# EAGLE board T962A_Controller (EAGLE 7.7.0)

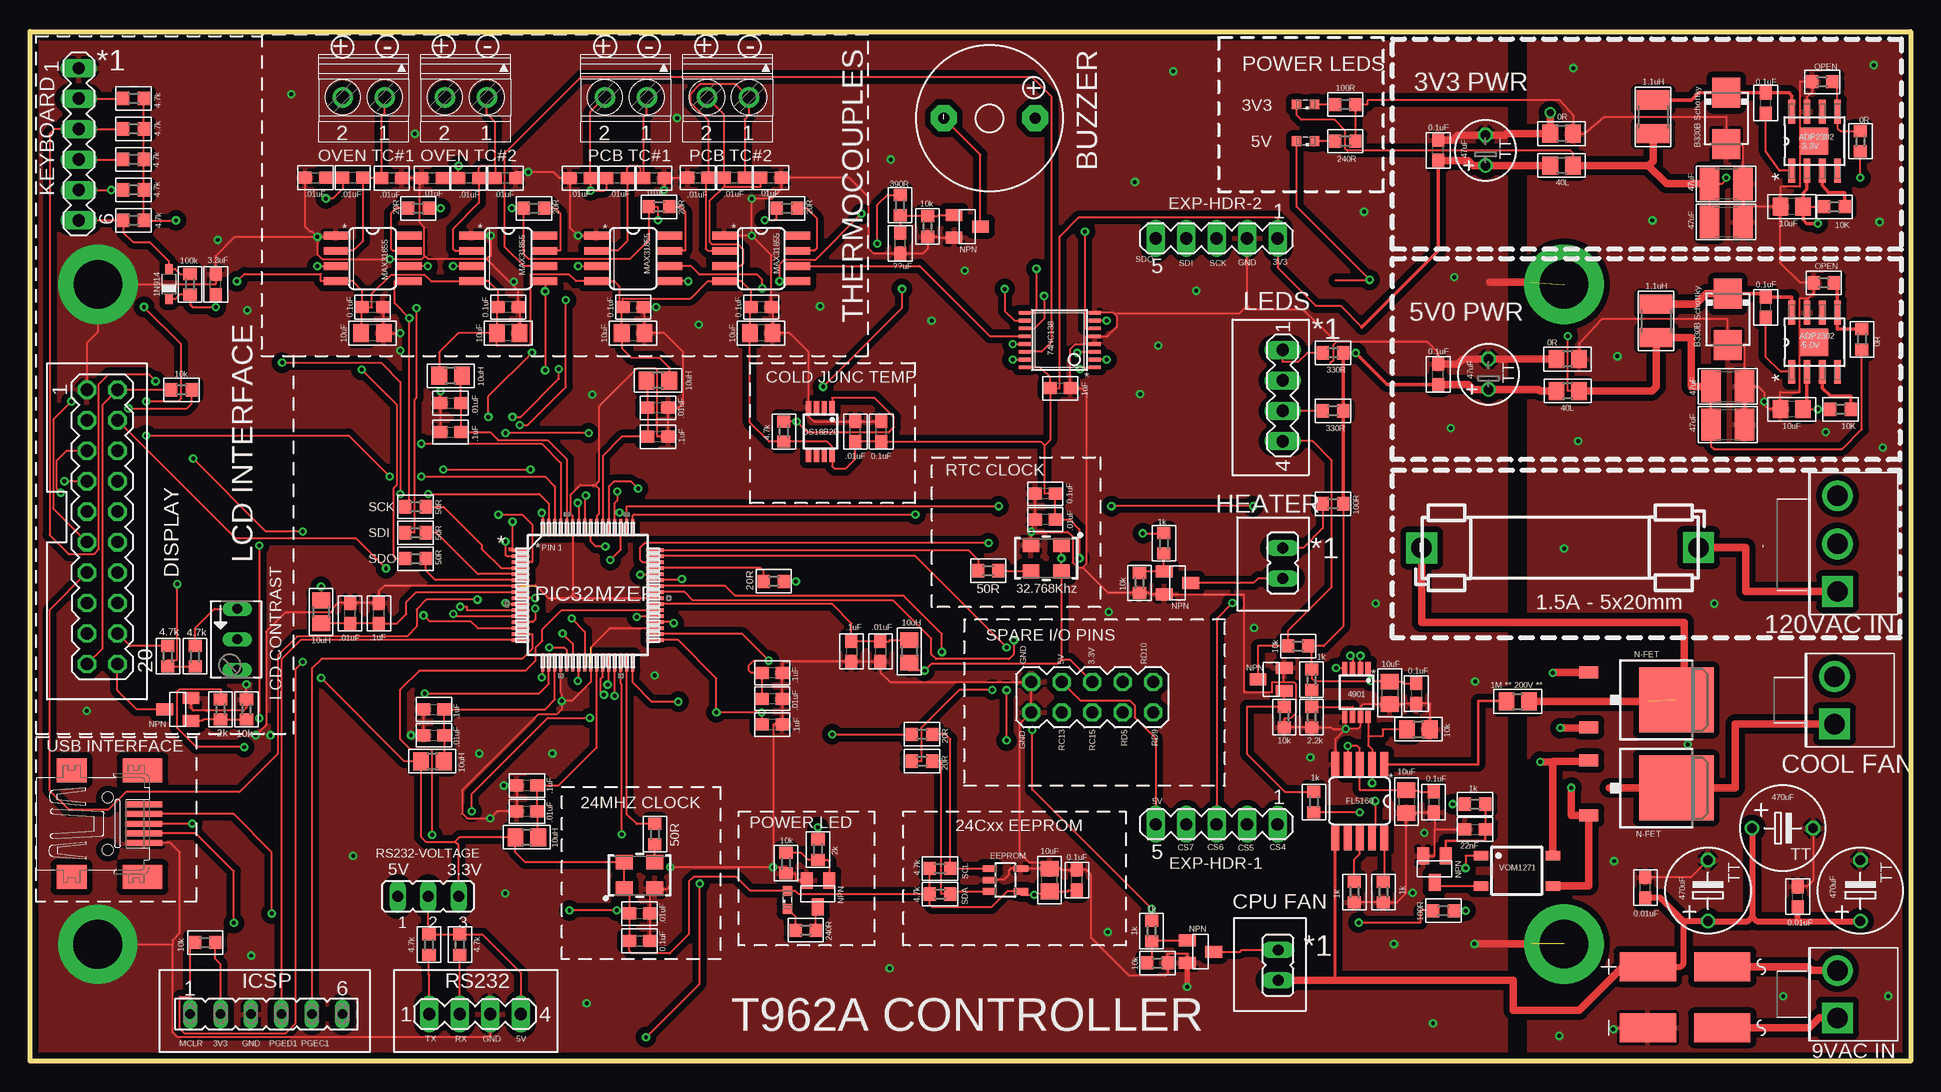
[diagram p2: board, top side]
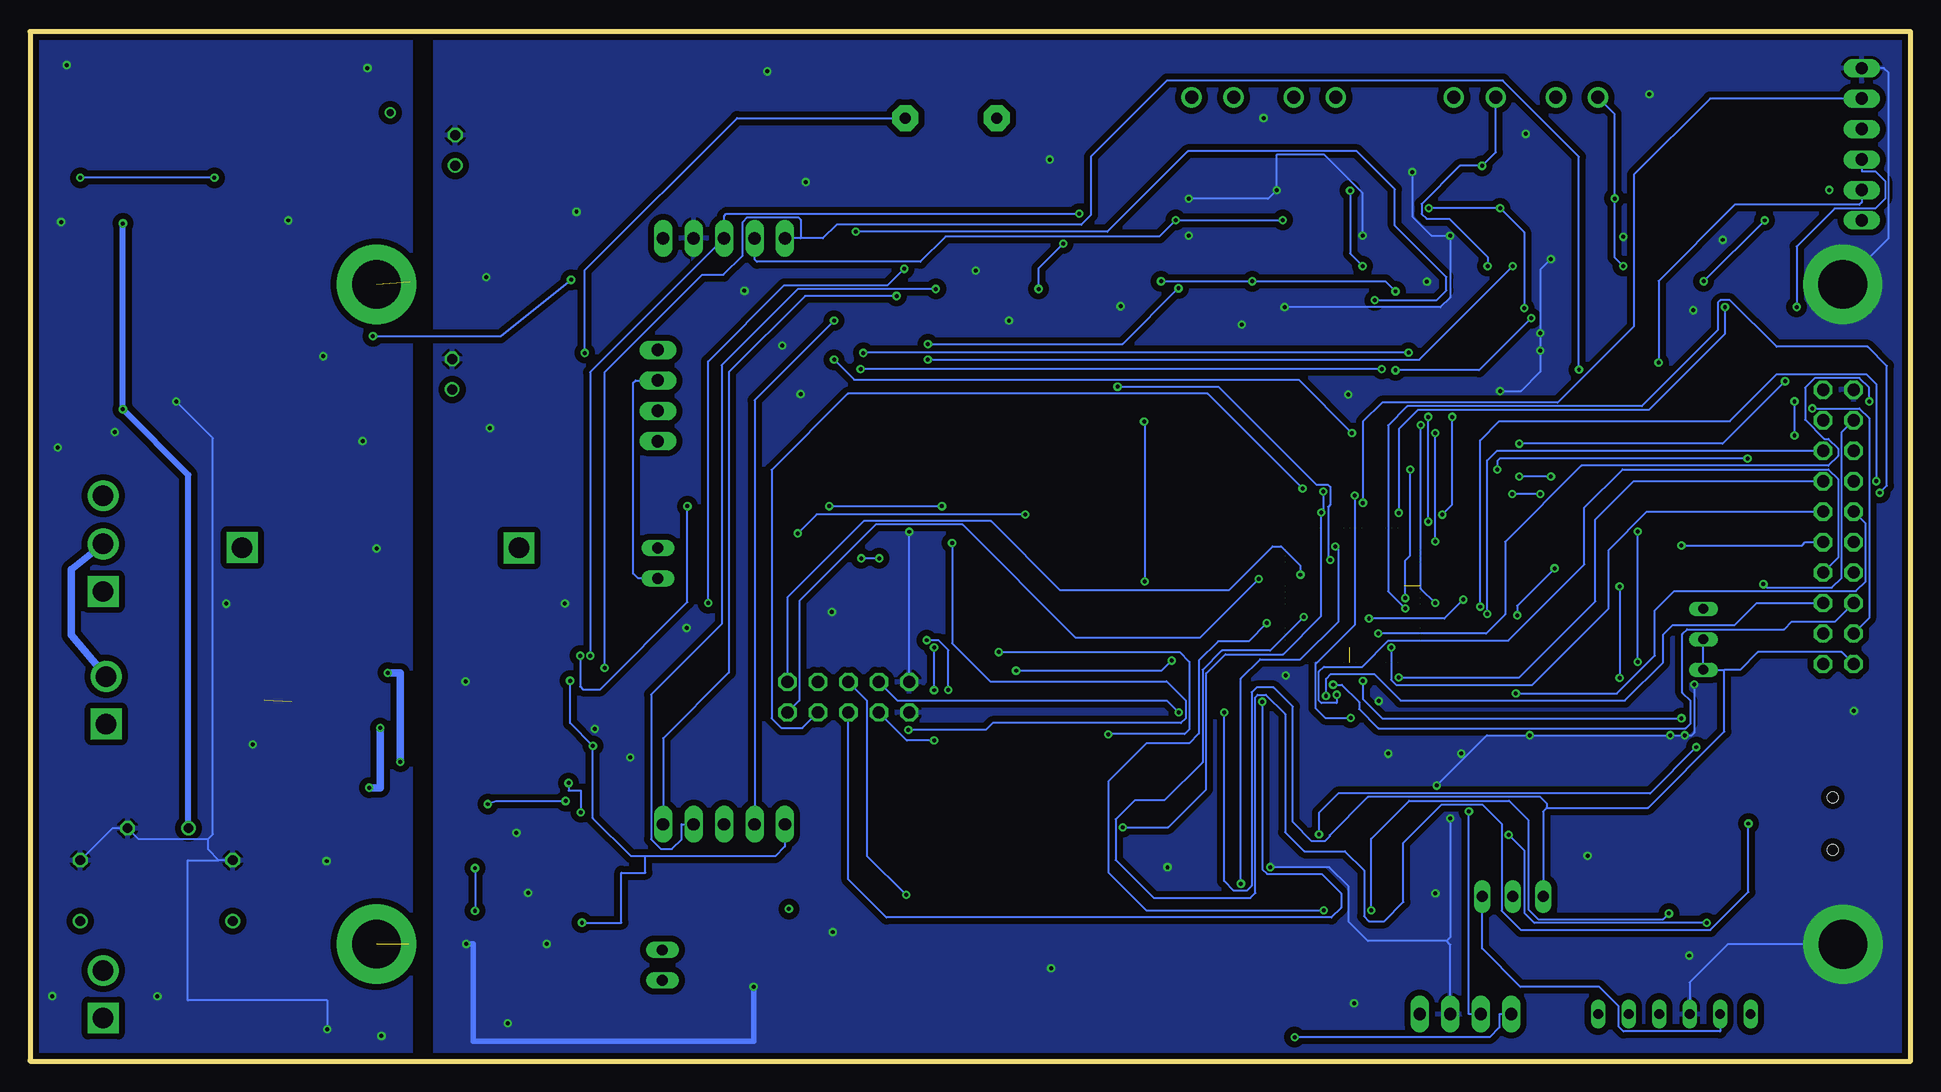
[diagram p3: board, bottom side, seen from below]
Size 156.72 x 86.03 mm. Coordinates in mm from the lower left corner, seen from the top.
Outline: 0,85.9 0.02,86.03 0.02,0 156.72,0.13
Outline: 0,85.9 0,0.05 156.72,0.05 156.72,0.13
Outline: 0,85.9 156.72,85.9 156.72,0.13
Copper layers (1*16): Top 0.035559375mm / dielectric 1.6mm / Bottom 0.035559375mm
Design rules "oshpark-2layer *": minimum track width 6mil, minimum drill 10mil, track to track 6mil, track to pad 6mil, pad to pad 6mil, via to via 6mil, smd to smd 6mil, copper to edge 15mil, drill to drill 6mil, minimum pad ring 5mil, minimum via ring 5mil, stop-mask expansion 2.5mil, vias tented up to drill 13mil, thermal gap 10mil
Net classes: 1 POWER: width 0.305 mm, clearance 0.305 mm

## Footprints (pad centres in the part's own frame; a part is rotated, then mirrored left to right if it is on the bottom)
Z4-D = smd 2.4 x 4.7: AC1 2.55,-3.1; AC2 -2.55,-3.1; VDD 2.55,3.1; VSS -2.55,3.1
TT5D7 = drill 0.813: + -2.54,0 | drill 0.813 octagon: - 2.54,0
C1210 = smd 1.6 x 2.7: 1 -1.4,0; 2 1.4,0
TT2D5 = drill 0.813: + -1.27,0 | drill 0.813 octagon: - 1.27,0
C0603 = smd 1.1 x 1: 1 -0.85,0; 2 0.85,0
C0805 = smd 1.3 x 1.5: 1 -0.95,0; 2 0.95,0
SOD323_ST = smd 0.8 x 0.6: A 1.25,0; C -1.25,0
FUSE_HOLDER_5X20MM_1.78MM = drill 1.707 square: 1 -2.565,0; 2 20.498,0.025
MSOP8 = smd 0.45 x 1: 1 -0.975,-2.05; 2 -0.325,-2.05; 3 0.325,-2.05; 4 0.975,-2.05; 5 0.975,2.05; 6 0.325,2.05; 7 -0.325,2.05; 8 -0.975,2.05
TSSOP16 = smd 0.305 x 0.991: 1 -2.275,-2.918; 2 -1.625,-2.918; 3 -0.975,-2.918; 4 -0.325,-2.918; 5 0.325,-2.918; 6 0.975,-2.918; 7 1.625,-2.918; 8 2.275,-2.918; 9 2.275,2.918; 10 1.625,2.918; 11 0.975,2.918; 12 0.325,2.918; 13 -0.325,2.918; 14 -0.975,2.918; 15 -1.625,2.918; 16 -2.275,2.918
SOT23-5L = smd 0.55 x 1.2: 1 -0.95,-1.3; 2 0,-1.3; 3 0.95,-1.3; 4 0.95,1.3; 5 -0.95,1.3
FE06 = drill 0.813 long: 1 -6.35,0; 2 -3.81,0; 3 -1.27,0; 4 1.27,0; 5 3.81,0; 6 6.35,0
KK41791-4020_3-PIN = drill 1.707 square: 1 -1.981,0 | drill 1.707: 2 1.981,0; 3 5.994,0
KK41791-4020_2-PIN = drill 1.707 square: 1 -1.981,0 | drill 1.707: 2 1.981,0
JP1 = drill 0.914 long: 1 0,-1.27; 2 0,1.27
JP2 = drill 0.914 long: 1 -2.54,0; 2 0,0; 3 2.54,0
L0805 = smd 1.3 x 1.5: 1 -0.95,0; 2 0.95,0
R1210 = smd 1.6 x 2.7: 1 -1.4,0; 2 1.4,0
SML0603 = smd 0.8 x 0.8: A 0.75,0; C -0.75,0
R0603 = smd 1 x 1.1: 1 -0.85,0; 2 0.85,0
R0805 = smd 1.3 x 1.5: 1 -0.95,0; 2 0.95,0
B64Y = drill 0.813 long: A 2.54,0; E -2.54,0; S 0,0
YHE12-XX-7.6MM = drill 0.914 pad 2.159 octagon: + 3.81,0.025; - -3.81,0.025
MA10-2 = drill 1.016 octagon: 1 -11.43,-1.27; 2 -11.43,1.27; 3 -8.89,-1.27; 4 -8.89,1.27; 5 -6.35,-1.27; 6 -6.35,1.27; 7 -3.81,-1.27; 8 -3.81,1.27; 9 -1.27,-1.27; 10 -1.27,1.27; 11 1.27,-1.27; 12 1.27,1.27; 13 3.81,-1.27; 14 3.81,1.27; 15 6.35,-1.27; 16 6.35,1.27; 17 8.89,-1.27; 18 8.89,1.27; 19 11.43,-1.27; 20 11.43,1.27
MA06-1 = drill 1.016 long: 1 -6.35,0; 2 -3.81,0; 3 -1.27,0; 4 1.27,0; 5 3.81,0; 6 6.35,0
MA04-1 = drill 1.016 long: 1 -3.81,0; 2 -1.27,0; 3 1.27,0; 4 3.81,0
MA05-2 = drill 1.016 octagon: 1 -5.08,-1.27; 2 -5.08,1.27; 3 -2.54,-1.27; 4 -2.54,1.27; 5 0,-1.27; 6 0,1.27; 7 2.54,-1.27; 8 2.54,1.27; 9 5.08,-1.27; 10 5.08,1.27
MA05-1 = drill 1.016 long: 1 -5.08,0; 2 -2.54,0; 3 0,0; 4 2.54,0; 5 5.08,0
SOT23-BEC = smd 1 x 1.4: B -0.95,-1.1; C 0,1.1; E 0.95,-1.1
SOIC127P600X175-9N = smd 1.981 x 0.559: 1 -2.464,1.905; 2 -2.464,0.635; 3 -2.464,-0.635; 4 -2.464,-1.905; 5 2.464,-1.905; 6 2.464,-0.635; 7 2.464,0.635; 8 2.464,1.905 | smd 2.286 x 2.286: 9 0,0
TQFP64_10X10MC = smd 1.473 x 0.279: 1 -5.613,3.75; 2 -5.613,3.25; 3 -5.613,2.75; 4 -5.613,2.25; 5 -5.613,1.75; 6 -5.613,1.25; 7 -5.613,0.75; 8 -5.613,0.25; 9 -5.613,-0.25; 10 -5.613,-0.75; 11 -5.613,-1.25; 12 -5.613,-1.75; 13 -5.613,-2.25; 14 -5.613,-2.75; 15 -5.613,-3.25; 16 -5.613,-3.75; 33 5.613,-3.75; 34 5.613,-3.25; 35 5.613,-2.75; 36 5.613,-2.25; 37 5.613,-1.75; 38 5.613,-1.25; 39 5.613,-0.75; 40 5.613,-0.25; 41 5.613,0.25; 42 5.613,0.75; 43 5.613,1.25; 44 5.613,1.75; 45 5.613,2.25; 46 5.613,2.75; 47 5.613,3.25; 48 5.613,3.75 | smd 0.279 x 1.473: 17 -3.75,-5.613; 18 -3.25,-5.613; 19 -2.75,-5.613; 20 -2.25,-5.613; 21 -1.75,-5.613; 22 -1.25,-5.613; 23 -0.75,-5.613; 24 -0.25,-5.613; 25 0.25,-5.613; 26 0.75,-5.613; 27 1.25,-5.613; 28 1.75,-5.613; 29 2.25,-5.613; 30 2.75,-5.613; 31 3.25,-5.613; 32 3.75,-5.613; 49 3.75,5.613; 50 3.25,5.613; 51 2.75,5.613; 52 2.25,5.613; 53 1.75,5.613; 54 1.25,5.613; 55 0.75,5.613; 56 0.25,5.613; 57 -0.25,5.613; 58 -0.75,5.613; 59 -1.25,5.613; 60 -1.75,5.613; 61 -2.25,5.613; 62 -2.75,5.613; 63 -3.25,5.613; 64 -3.75,5.613
DO214AA-SMB = smd 2.5 x 2.3: A 2.15,0; C -2.15,0
SO08 = smd 0.66 x 2.032: 1 -1.905,-3.073; 2 -0.635,-3.073; 3 0.635,-3.073; 4 1.905,-3.073; 5 1.905,3.073; 6 0.635,3.073; 7 -0.635,3.073; 8 -1.905,3.073
SOP10 = smd 0.66 x 2.032: 1 -2.057,-3.073; 2 -1.041,-3.073; 3 -0.025,-3.073; 4 0.991,-3.073; 5 2.007,-3.073; 6 2.007,3.073; 7 0.991,3.073; 8 -0.025,3.073; 9 -1.041,3.073; 10 -2.057,3.073
DPACK_3 = smd 1 x 1.6: 1 -2.28,-4.8; 3 2.28,-4.8 | smd 5.4 x 6.2: 4 0,2.5
SOP04 = smd 0.8 x 1.2: 1 -1.27,-3; 2 1.27,-3; 3 1.27,3; 4 -1.27,3
1751248 = drill 1.1 pad 1.7: 1 -1.75,-0.1; 2 1.75,-0.1
32005-201 = smd 3.1 x 0.5: 1 3,1.6; 2 3,0.8; 3 3,0; 4 3,-0.8; 5 3,-1.6 | smd 2.5 x 2: M1 -3,-4.45; M2 -3,4.45 | smd 3.3 x 2: M3 2.9,4.45; M4 2.9,-4.45 | hole 0.9: 0,2.2; 0,-2.2
OSCILLATOR-SMD-5X3.2 = smd 1.397 x 1.194: 1 -1.27,-1.1; 2 1.27,-1.1; 3 1.27,1.1; 4 -1.27,1.1

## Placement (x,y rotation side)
B1  Z4DGP406L-HF  [Z4-D]  137.92,5.38 90 top
C1  470uF  [TT5D7]  146.05,19.48 0 top
C2  47uF  [C1210]  141.48,56.31 0 top
C3  47uF  [TT2D5]  121.28,76 90 top
C4  47uF  [C1210]  141.48,53.14 0 top
C5  0.1uF  [C0603]  144.65,62.92 90 top
C6  470uF  [TT5D7]  152.53,14.27 90 top
C7  10uF  [C0805]  146.81,54.41 180 top
C8  0.1uF  [C0603]  50.8,10.08 0 top
C9  470uF  [TT5D7]  139.83,14.27 90 top
C10  22nf  [C0603]  120.42,19.38 0 top
C11  47uF  [TT2D5]  121.54,57.33 90 top
C12  0.01uF  [C0603]  50.8,12.37 0 top
C13  .01uF  [C0603]  134.62,14.53 90 top
C14  47uF  [C1210]  141.35,70.03 0 top
C15  47uF  [C1210]  141.35,73.2 0 top
C16  0.1uF  [C0603]  117.35,76 90 top
C17  0.1uF  [C0603]  117.35,57.33 90 top
C18  0.01uF  [C0603]  68.78,52.55 90 top
C19  0.1uF  [C0603]  144.65,79.93 90 top
C20  10uF  [C0805]  146.81,71.3 180 top
C21  0.1uF  [C0603]  35.05,52.5 0 top
C22  0.1uF  [C0603]  52.32,52.12 0 top
C23  0.1uF  [C0603]  68.45,34.21 270 top
C24  0.1uF  [C0603]  84.61,47.37 180 top
C25  0.01uF  [C0603]  84.61,45.21 180 top
C26  0.1uF  [C0603]  29.08,37.39 90 top
C27  0.1uF  [C0603]  33.66,29.39 0 top
C28  0.1uF  [C0603]  41.4,23.04 180 top
C29  0.01uF  [C0603]  26.67,37.39 90 top
C30  0.1uF  [C0603]  70.94,52.55 90 top
C31  0.1uF  [C0603]  85.85,56.16 0 top
C32  0.1uF  [C0603]  60.93,62.92 180 top
C33  0.1uF  [C0603]  50.27,62.92 180 top
C34  0.01uF  [C0603]  33.66,27.23 0 top
C35  0.1uF  [C0603]  39.85,62.92 180 top
C36  0.1uF  [C0603]  28.55,62.92 180 top
C37  0.01uF  [C0603]  41.4,20.88 180 top
C38  0.01uF  [C0603]  70.87,34.21 270 top
C39  0.1uF  [C0603]  87.25,15.16 90 top
C40  0.01uF  [C0603]  52.32,54.53 0 top
C41  0.01uF  [C0603]  35.05,54.92 0 top
C42  0.1uF  [C0603]  61.85,32.44 180 top
C43  0.01uF  [C0603]  61.85,30.28 180 top
C44  0.1uF  [C0603]  61.85,28.12 180 top
C45  ??? UNSURE ???  [C0603]  72.52,68.25 90 top
C46  10uF  [C0805]  60.93,60.76 180 top
C47  10uF  [C0805]  50.27,60.76 180 top
C48  0.01uF  [C0603]  23.8,73.71 0 top
C49  10uF  [C0805]  39.85,60.76 180 top
C50  .01uF  [C0603]  147.32,13.77 90 top
C51  10uF  [C0805]  28.55,60.76 180 top
C52  0.01uF  [C0603]  30.15,73.69 180 top
C53  0.01uF  [C0603]  26.9,73.71 180 top
C54  0.01uF  [C0603]  36.55,73.69 180 top
C55  0.01uF  [C0603]  33.5,73.69 0 top
C56  0.01uF  [C0603]  39.62,73.69 180 top
C57  0.01uF  [C0603]  48.92,73.69 180 top
C58  0.01uF  [C0603]  45.85,73.69 0 top
C59  10uF  [C0805]  84.96,15.16 90 top
C60  0.01uF  [C0603]  51.99,73.69 180 top
C61  0.01uF  [C0603]  58.7,73.71 180 top
C62  0.01uF  [C0603]  61.75,73.71 180 top
C63  0.01uF  [C0603]  55.65,73.71 0 top
C66  3.3uF  [C0603]  15.47,64.82 90 top
C67  0.1uF  [C0603]  115.52,30.71 270 top
C68  10uF  [C0805]  113.31,30.76 270 top
C69  0.1uF  [C0603]  116.97,21.67 270 top
C70  10uF  [C0805]  114.71,21.69 270 top
D1  1N914  [SOD323_ST]  11.58,64.85 90 top
F1  FUSE  [FUSE_HOLDER_5X20MM_1.78MM]  118.54,42.85 0 top
IC1  MCP4901MS  [MSOP8]  110.54,30.81 180 top
IC2  74138TSSOP  [TSSOP16]  85.8,60.17 90 top
IC3  AT24C_SINGLE  [SOT23-5L]  81.28,15.16 270 top
ICSP  [FE06]  19.68,3.99 0 top
J1  0026604030  [KK41791-4020_3-PIN]  150.62,41.2 90 top
J2  0026604020  [KK41791-4020_2-PIN]  150.62,5.64 90 top
J3  0026604020  [KK41791-4020_2-PIN]  150.37,30.15 90 top
JP1  [JP1]  104.01,8.05 180 top
JP2  [JP1]  104.39,41.58 0 top
JP3  [JP2]  33.17,13.79 0 top
L1  40R  [L0805]  128.14,55.93 180 top
L5  1.1uH  [R1210]  135.51,61.77 270 top
L6  40R  [L0805]  127.63,74.73 180 top
L7  1.1uH  [R1210]  135.25,78.79 270 top
L8  10uH  [L0805]  24.26,37.52 270 top
L9  10uH  [L0805]  73.28,34.21 270 top
L10  10uH  [L0805]  35.05,57.2 180 top
L11  10uH  [L0805]  52.32,56.82 180 top
L12  10uH  [L0805]  33.53,25.07 0 top
L13  10uH  [L0805]  41.4,18.72 180 top
LED1  [SML0603]  106.3,79.81 180 top
LED2  [SML0603]  63.12,13.51 90 top
LED5  [SML0603]  106.3,76.76 180 top
R1  4.7k  [R0603]  8.64,70.16 180 top
R2  100R  [R0603]  109.6,79.81 0 top
R3  4.7K  [R0603]  62.81,52.55 90 top
R4  4.7k  [R0603]  8.64,72.7 180 top
R5  240R  [R0603]  109.6,76.76 180 top
R6  0R  [R0805]  127.63,77.39 180 top
R7  10K  [R0603]  150.37,71.3 0 top
R8  10K  [R0603]  150.88,54.41 0 top
R9  *OPEN*  [R0603]  149.35,81.71 180 top
R10  0R  [R0603]  152.53,76.76 90 top
R11  *OPEN*  [R0603]  149.48,64.95 180 top
R12  0R  [R0603]  152.65,60.25 90 top
R13  50R  [R0603]  79.86,40.94 0 top
R14  50R  [R0603]  52.07,18.97 270 top
R15  10k  [R0603]  14.61,9.96 0 top
R16  20R  [R0603]  74.32,27.31 0 top
R17  20R  [R0603]  74.32,25.07 0 top
R18  4.7k  [R0603]  33.25,9.78 270 top
R19  10k  [R0805]  115.7,27.74 0 top
R20  1k  [R0603]  120.42,21.49 0 top
R21  4.7k  [R0603]  8.64,75.23 180 top
R22  100k  [R0603]  13.33,64.82 270 top
R23  4.7k  [R0603]  8.64,77.78 180 top
R24  4.7k  [R0603]  35.81,9.78 270 top
R25  100R  [R0603]  117.78,12.6 180 top
R27  20R  [R0603]  32.36,71.17 180 top
R28  2k  [R0603]  65.66,17.7 90 top
R29  240  [R0603]  64.64,10.97 0 top
R30  10k  [R0603]  62.99,16.56 90 top
R31  20R  [R0603]  61.98,40.06 0 top
R32  20R  [R0603]  42.01,71.17 0 top
R33  20R  [R0603]  52.43,71.3 0 top
R34  20R  [R0603]  63.09,71.17 0 top
R35  50R  [R0603]  32.13,41.96 180 top
R36  50R  [R0603]  32.13,44.12 180 top
R37  50R  [R0603]  32.13,46.28 180 top
R38  4.7K  [R0603]  75.84,14 180 top
R39  0R  [R0805]  128.14,58.6 180 top
R40  1M  [R0805]  123.98,30.05 0 top
R41  4.7K  [R0603]  75.84,16.13 180 top
R42  10k  [R0603]  74.8,69.65 90 top
R43  390R  [R0603]  72.52,71.42 90 top
R44  10k  [R0603]  104.52,28.75 270 top
R45  2k  [R0603]  15.88,29.39 90 top
R46  10k  [R0603]  18.03,29.39 90 top
R47  4.7k  [R0603]  8.64,80.31 180 top
R48  10k  [B64Y]  17.27,35.23 270 top
R49  4.7k  [R0603]  13.77,33.81 270 top
R50  4.7k  [R0603]  11.48,33.81 90 top
R51  10k  [R0603]  12.62,56.03 0 top
R52  1k  [R0603]  93.47,10.9 270 top
R53  10k  [R0603]  93.95,8.26 180 top
R54  1k  [R0603]  94.49,43.23 270 top
R55  10k  [R0603]  92.46,39.93 90 top
R56  330R  [R0603]  108.58,59.11 180 top
R57  330R  [R0603]  108.58,54.28 180 top
R58  10k  [R0603]  105.69,34.67 0 top
R59  1k  [R0603]  106.81,31.88 90 top
R60  2.2k  [R0603]  106.81,28.75 90 top
R61  100R  [R0603]  108.58,46.53 180 top
R62  1k  [R0603]  110.36,14.15 90 top
R63  1k  [R0603]  112.78,14.15 90 top
R64  1k  [R0603]  106.98,21.67 90 top
SG1  YHE12-XX7.6MM  [YHE12-XX-7.6MM]  79.96,78.66 0 top
SV1  [MA10-2]  6.02,44.6 270 top
SV2  [MA06-1]  4.06,76.51 270 top
SV3  [MA04-1]  104.39,55.55 270 top
SV4  [MA05-2]  88.52,30.4 0 top
SV5  RS232  [MA04-1]  37.08,3.99 0 top
SV6  EXP-HDR-1  [MA05-1]  98.88,19.81 180 top
SV7  EXP-HDR-2  [MA05-1]  98.88,68.66 180 top
T1  BC817-16LT1SMD  [SOT23-BEC]  78.11,69.65 270 top
T2  BC817-16LT1SMD  [SOT23-BEC]  12.32,29.39 90 top
T3  BC817-16LT1SMD  [SOT23-BEC]  65.66,14.02 180 top
T4  BC817-16LT1SMD  [SOT23-BEC]  97.54,9.2 270 top
T5  BC817-16LT1SMD  [SOT23-BEC]  95.63,39.93 270 top
T6  BC817-16LT1SMD  [SOT23-BEC]  117.04,16.08 180 top
T7  BC817-16LT1SMD  [SOT23-BEC]  103.43,31.88 90 top
U1  ADP2302ARDZ-5.0-R7  [SOIC127P600X175-9N]  148.72,60 90 top
U2  ADP2302ARDZ-5.0-R7  [SOIC127P600X175-9N]  148.72,76.76 90 top
U4  PIC32MZXXXXEC(G/H/M)064-I/PT  [TQFP64_10X10MC]  46.48,38.91 0 top
U$1  DIODE-SMB  [DO214AA-SMB]  141.48,61.9 270 top
U$2  MAX31855  [SO08]  28.55,66.98 270 top
U$3  DIODE-SMB  [DO214AA-SMB]  141.35,78.66 270 top
U$4  MAX31855  [SO08]  39.85,66.98 270 top
U$5  MAX31855  [SO08]  50.27,66.98 270 top
U$6  MAX31855  [SO08]  60.93,66.98 270 top
U$7  FL5160SOP10  [SOP10]  110.79,21.74 180 top
U$8  DS18B20MSOP8  [MSOP8]  65.86,52.55 180 top
U$9  N-PWR-MOSFETDPAK3  [DPACK_3]  134.7,22.83 270 top
U$10  N-PWR-MOSFETDPAK3  [DPACK_3]  134.7,30.18 270 top
U$11  VOM1271  [SOP04]  123.9,15.93 270 top
X1  1751248  [1751248]  27.81,80.31 180 top
X2  1751248  [1751248]  36.32,80.31 180 top
X3  1751248  [1751248]  49.66,80.31 180 top
X4  1751248  [1751248]  58.17,80.31 180 top
X5  MINI-USB-32005-201  [32005-201]  6.48,19.86 0 top
Y1  OSCILLATORSMD-5X3  [OSCILLATOR-SMD-5X3.2]  50.8,15.54 0 top
Y2  OSCILLATORSMD-5X3  [OSCILLATOR-SMD-5X3.2]  84.68,41.99 180 top

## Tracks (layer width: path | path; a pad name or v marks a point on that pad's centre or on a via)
3V3_VDD  (via drill 0.33 pad 0.69)  (1 unrouted)
  Top 0.152: 49.32,62.92 C47.2 49.32,59.5 50.11,58.7 52.46,58.7 53.27,57.89 L11.1 | 49.32,62.92 49.11,62.92 49.11,64.67 48.7,65.08 U$5.4 45.52,65.08 44.96,65.63 41.68,65.63 41.68,59.87 41.53,59.72 38.9,59.72 C49.2 | C31.1 85.8,56.16 85.8,68.81 87.4,70.41 103.96,70.41 SV7.1 103.96,66.22 107.14,63.04 109.22,63.04 111,61.27 | 84.56,51.38 84.24,51.7 C30.1 C18.1 68.78,50.27 67.97,49.45 67.06,49.45 66.84,49.67 U$8.8 66.84,51.29 66.42,51.7 R3.1 61.6,51.7 59.98,53.31 C46.2 59.98,62.92 C32.2 60.09,64.27 59.28,65.08 U$6.4 56.46,65.08 55.04,63.65 49.42,63.65 C33.2 49.32,62.92 | R38.2 64.02,14 63.75,14.26 LED2.A 60.02,14.26 58.84,15.44 55.32,15.44 54.91,15.04 54.91,10.64 53.31,9.04 50.15,9.04 49.95,9.25 C8.1 C12.1 49.95,14.45 Y1.1 Y1.4 41.26,16.64 40.45,17.45 L13.2 35.79,18.72 35.41,18.34 | 85.95,33.5 85.65,33.2 75.13,33.2 v74.55,32.61 73.28,32.61 L9.2 | 35.41,18.34 32.99,18.34 32.58,18.76 L12.1 31.19,25.07 v24.26,32 | C49.2 35.7,60.76 34.1,59.16 L10.2 | ICSP.2 15.88,8.15 15.45,8.57 R15.2 | 84.56,51.38 84.56,47.37 C24.1 C25.1 86.64,45.21 87.45,44.4 v87.45,41.99 | C31.1 85,51.83 84.56,51.38 | JP3.3 35.71,18.03 35.41,18.34 | R47.1 R23.1 R21.1 R4.1 R1.1 v12.17,70.16 | C49.2 38.9,62.92 C35.2 39,64.27 38.2,65.08 U$4.4 33.43,65.08 32.87,65.63 30.1,65.63 28.5,64.03 28.5,62.92 C36.2 | C36.2 27.6,62.92 C51.2 | C43.2 C42.2 60.1,32.44 59.89,32.64 59.89,33.05 60.3,33.45 v61.57,33.45 59.36,35.66 U4.34 | R38.2 R41.2 | v24.26,39.62 L8.1 | R38.2 74.99,13.11 75.2,12.9 80.12,12.9 81.43,14.21 IC3.4 82.58,13.92 v83.69,13.92 83.77,14 84.96,14 C59.1 86.54,14.21 86.54,14.31 C39.1
  Top 0.152: 85.95,33.5 Y2.4 v85.95,41.99 Y2.1 | SV4.6 86.69,33.5 85.95,33.5 | C36.2 27.7,64.27 26.9,65.08 U$2.4 24.23,65.08 24.23,65.69 17.86,65.69 v17.25,65.08 | C31.1 85,57.1 84.2,57.9 IC2.16
  Top 0.305: 111,61.27 117.35,67.62 C16.1
  Top 0.61: L6.2 C3.+ 120.27,74.73 119.85,75.15 C16.1
  Bottom 0.152: ICSP.2 15.88,2.54 23.93,2.54 24.33,2.95 24.33,4.65 25.93,6.25 32.51,6.25 35.71,9.45 JP3.3 | v85.95,41.99 v87.45,41.99 | v24.26,39.62 v24.26,32 | SV4.6 86.97,30.12 86.97,17.2 v83.69,13.92 | v74.55,32.61 62.41,32.61 v61.57,33.45 | v12.17,70.16 v17.25,65.08
5V0_VDD  (via drill 0.33 pad 0.69)  (1 unrouted)
  Top 0.152: 125.73,56.06 125.86,55.93 | R61.1 109.44,36.28 107.82,34.67 106.81,34.67 | 106.81,34.67 R59.2 106.81,31.98 107.01,31.78 v111.71,31.78 | 106.81,34.67 R58.2 | C69.1 115.82,22.52 115.7,22.64 C70.1 110.82,22.64 U$7.3 110.82,26.14 110.62,26.34 v109.8,26.34 U$7.4 | v111.71,31.78 111.78,31.71 C68.1 114.3,31.71 114.45,31.56 C67.1 | C44.2 61,29.12 v60.98,29.13 v57.2,29.13 57.2,31.99 54.03,35.16 U4.33 | SV4.4 87.53,30.12 91.64,30.12 92.05,29.72 92.05,28.73 93.8,26.97 SV6.5 | R51.1 SV1.2 6.04,54.79 6.04,34.47 SV1.19 | v111.71,31.78 111.63,31.85 111.63,32.86 IC1.1 | R25.2 116.88,12.65 115.88,12.65 115.88,11.61 v110.72,11.61
  Top 0.305: C17.1 113.12,56.48 v110.49,59.11 R56.1 R57.1 R61.1
  Top 0.61: 125.73,56.06 C11.+ 120.27,56.06 119.85,56.48 C17.1 | 125.86,55.93 L1.2
  Bottom 0.152: 30.33,21.18 21.87,21.18 15.52,27.53 15.52,32.69 | SV1.19 5.74,34.16 12.72,34.16 14.2,32.69 15.52,32.69 | v110.49,59.11 110.49,65.99 97.79,78.69 SG1.+ | v57.2,29.13 57.2,15.09 56.39,14.27 55.32,14.27 54.91,14.68 54.91,30.81 54.51,31.22 53.09,31.22 51.49,29.62 51.49,19.99 49.89,18.39 48.82,18.39 48.41,18.8 48.41,18.9 45.24,22.07 30.85,22.07 30.33,21.55 30.33,21.18 | 15.52,32.69 R48.A R48.S | 30.33,21.18 30.63,20.88 JP3.1 | SV6.5 93.8,17.96 94.61,17.14 105.44,17.14 | 105.44,17.14 106.63,17.14 109.8,20.32 v109.8,26.34 111.71,28.25 v111.71,31.78 | SV4.4 84.43,30.12 61.98,30.12 v60.98,29.13 | v110.72,11.61 107.44,11.61 107.44,15.77 105.44,15.77 105.44,17.14
!CS0  (via drill 0.33 pad 0.69)
  Top 0.152: v33.15,66.34 U$2.6 | v81.89,58.55 IC2.15
  Bottom 0.152: v81.89,58.55 40.95,58.55 v33.15,66.34
!CS1
  Top 0.152: U$4.6 41.17,66.34 39.57,67.95 39.57,75.77 45.92,82.12 83.49,82.12 85.09,80.52 85.09,60 84.29,59.2 IC2.14
!CS2  (via drill 0.33 pad 0.69)
  Top 0.152: v61.01,64.49 61.01,65.23 60.6,65.63 55.8,65.63 55.09,66.34 U$5.6 | v81.89,59.84 v81.89,59.85 IC2.13
  Bottom 0.152: v81.89,59.84 65.66,59.84 v61.01,64.49
!CS3
  Top 0.152: U$6.6 74.14,66.34 79.98,60.5 IC2.12
!CS4  (via drill 0.33 pad 0.69)
  Top 0.152: v84.51,63.86 84.51,61.96 83.69,61.15 IC2.11
  Bottom 0.152: v84.51,63.86 92.13,63.86 98.48,57.51 98.48,32.46 103.96,26.97 SV6.1
!CS5  (via drill 0.33 pad 0.69)
  Top 0.152: v81.23,64.44 81.23,62.61 82.04,61.8 IC2.10
  Bottom 0.152: v81.23,64.44 92.73,64.44 99.08,58.09 99.08,36.5 104.95,30.63 104.95,18.57 104.14,17.75 103.23,17.75 102.41,18.57 102.41,19.81 SV6.2
!CS6  (via drill 0.33 pad 0.69)
  Top 0.152: v83.87,66.12 83.87,62.65 83.67,62.45 IC2.9 | v100.2,38.25 98.88,36.93 SV6.3
  Bottom 0.152: v100.2,38.25 100.2,58.4 93.85,64.75 85.24,64.75 v83.87,66.12
!CS7  (via drill 0.33 pad 0.69)
  Top 0.152: v89.71,61.8 IC2.7
  Bottom 0.152: v89.71,61.8 96.34,55.17 SV6.4
A_3V3  (via drill 0.33 pad 0.69)
  Top 0.152: L6.1 128.59,75.77 128.4,75.95 109.77,75.95 109.6,76.12 109.6,77.65 108.71,78.54 105.95,78.54 105.55,78.94 LED1.A | C14.1 C15.1 141.01,73.2 141.35,73.55 v141.35,73.71 | v152.53,73.71 R10.1
  Top 0.61: L6.1 134.87,74.73 | C15.1 136.4,73.2 134.87,74.73 | 134.87,74.73 135.25,75.11 L7.2
  Bottom 0.152: v141.35,73.71 v152.53,73.71
A_5V0  (via drill 0.33 pad 0.69)
  Top 0.152: R12.1 152.65,52.76 151,51.11 140.34,51.11 140.08,51.36 C4.1 C2.1 | 108.78,65.15 111.58,65.15 v111.63,65.2 105.55,71.29 LED5.A | L1.1 128.14,55.93 v128.14,60.5
  Top 0.61: L1.1 135.13,55.93 135.51,56.31 L5.2 138.43,60.37 138.43,56.31 C2.1
  Bottom 0.152: v128.14,60.5 117.5,60.5 v111.63,65.2
AC_DC_IN  (via drill 0.33 pad 0.69)
  Top 0.152: C20.1 148.72,71.3 | 148.72,71.3 | 148.72,71.3 R7.1 | C20.1 | C7.1 148.08,54.41 v148.97,54.41 R8.1
  Top 0.254: 108.79,6.78 U$7.6
  Top 0.305: U2.2 148.08,72.76 147.76,72.44 C20.1 147.76,70.22 148.08,69.9 v148.97,69.9 | 148.08,54.41 U1.2
  Top 0.508: 143.51,12.12 143.89,11.73 147.32,11.73 | 147.32,11.73 C6.+ | C1.+ 143.51,12.12 | 137.79,11.73 135.85,13.68 C13.1 | 137.79,11.73 C9.+ 143.13,11.73 143.51,12.12 | B1.VDD 137.55,7.94 137.79,8.18 137.79,11.73 | 147.32,11.73 C50.1
  Top 0.61: B1.VDD 132.72,7.94 129.11,4.32 123.6,4.32 123.6,6.78 108.79,6.78 JP1.2
  Bottom 0.508: C1.+ 143.51,48.95 v148.97,54.41 v148.97,69.9
AC_IN1
  Top 0.61: B1.AC1 148.15,7.94 148.46,7.62 J2.2
AC_IN2
  Top 0.61: B1.AC2 148.28,2.83 149.1,3.66 J2.1
AGND  (via drill 0.33 pad 0.69)
  Top 0.152: 148.08,63.68 147.5,63.68 147.5,55.86 145.87,55.86 145.86,55.42 C7.2 144.87,54.41 144.53,54.75 v144.53,55.04 144.53,55.8 144.02,56.31 C2.2 | 148.08,63.68 148.21,63.68 148.63,64.1 R11.2 147.51,64.95 145.86,66.6 C20.2 | C20.2 142.75,71.3 | 142.75,71.3 C15.2 142.75,76.51 U$3.A 141.35,78.82 131.19,78.82 129.54,77.39 R6.1 128.59,78.92 127.49,80.16 111.45,80.16 111.45,79.81 R2.2 R5.1 | C20.2 145.86,72.95 147.5,72.95 147.5,81.71 R9.2 148.5,80.86 148.08,80.44 U2.7 | R39.1 129.09,59.87 131,61.92 141.48,61.92 U$1.A 142.88,59.75 C2.2 | 148.08,63.68 U1.7 | C9.- 138.39,15.38 C13.2 | C1.- 148.59,15.12 148.08,14.62 C50.2 | 142.75,71.3 C14.2 | C2.2 C4.2 | v131.95,2.72 132.07,2.83 B1.VSS
  Bottom 0.152: 141.86,18.59 147.7,18.59 C1.- 149.86,19.48 C6.- | C9.- 140.97,16.82 | 140.97,16.82 141.86,17.7 141.86,18.59 | 141.86,18.59 141.48,18.97 141.48,51.99 v144.53,55.04 | v131.95,2.72 131.95,5.13 143.56,5.13 143.56,16.82 140.97,16.82
  other vias: 129.01,51.77 140.36,38.2 128.6,82.86 154.13,70.03 132,16.74 154.41,51.21 132.28,58.83 135.2,70.16 153.64,83.11 138.15,26.47 127.84,42.8 149.66,52.5 146.1,5.46 154.86,5.49 127.43,2.16
  pour Top (isolate 0.508): 124.99,85.9 156.72,85.9 156.72,0.05 124.99,0.05
  pour Bottom (isolate 0.508): 124.99,85.9 156.72,85.9 156.72,0.05 124.99,0.05
CJ_IO  (via drill 0.33 pad 0.69)
  Top 0.152: U$8.1 66.84,55.35 70.38,55.35 71.98,53.75 71.98,52.91 71.58,52.5 64.77,52.5 v63.88,53.39 63.87,53.4 R3.2 | v63.83,40.06 R31.2
  Bottom 0.152: v63.88,53.39 63.83,53.34 v63.83,40.06
CLK
  Top 0.152: Y1.3 R14.2
CLK1
  Top 0.152: Y2.3 81.52,40.89 81.46,40.94 R13.2
CLK_PIC  (1 unrouted)
  Top 0.152: R14.1 50.55,19.82 49.73,20.64 U4.31
D+  (via drill 0.33 pad 0.69)
  Top 0.152: v13.51,19.86 X5.3 | v50.57,37.08 50.65,37.16 U4.37
  Bottom 0.152: v50.57,37.08 53.37,34.29 57.4,34.29 59,32.69 59,24.98 62.18,21.81 64.65,21.81 66.24,20.22 66.24,16.84 63.07,13.66 55.02,13.66 54.61,14.07 54.61,30.4 54.41,30.61 53.72,30.61 52.12,29.01 52.12,19.15 50.52,17.56 47.15,17.56 45.54,15.95 45.54,12.14 45.14,11.73 43.86,11.73 42.26,13.34 42.26,18.27 39.06,21.46 35.69,21.46 34.09,19.86 34.09,12.6 32.49,11 16.69,11 13.51,14.17 v13.51,19.86
D-  (via drill 0.33 pad 0.69)
  Top 0.152: v20.14,12.37 20.14,17.49 16.97,20.66 X5.2 | v48.89,12.62 v44.96,12.62 | v53.64,36.58 53.56,36.66 U4.36
  Bottom 0.152: v44.96,12.62 44.96,18.59 41.78,21.77 33.45,21.77 31.85,20.17 31.85,12.7 31.04,11.89 20.62,11.89 v20.14,12.37 | v53.64,36.58 55.17,35.05 57.71,35.05 59.31,33.45 59.31,27.38 60.12,26.57 63.68,26.57 66.85,23.39 66.85,15.8 63.68,12.62 v48.89,12.62
EEP_SCL
  Top 0.152: R16.2 76.28,27.3 76.69,26.89 R41.1 78.23,16.13 78.25,16.11 IC3.1
EEP_SDA
  Top 0.152: R17.2 75.92,25.07 75.92,14 R38.1 76.69,14.21 IC3.3
GND  (via drill 0.33 pad 0.69, 0.6 pad 0.69, 4.06 pad 6.6)  (7 unrouted)
  Top 0.152: 122.94,77.27 123.06,77.39 | C17.2 117.35,59.11 116.46,60 108.84,60 | 108.84,60 108.58,59.74 108.58,58.47 108.33,58.22 | 87.99,59.85 87.99,60.5 IC2.5 89.78,60.5 90.6,61.32 90.6,62.13 90.3,62.43 | 87.99,59.85 87.12,59.85 86.7,59.43 C31.2 87.63,56.16 88.04,55.75 88.04,41.5 87.73,41.2 | 51.22,62.92 C47.1 52.86,60.76 54.46,59.16 54.46,54.94 54.05,54.53 C40.2 C22.2 52.27,52.12 52.27,57.66 52.12,57.81 50.57,57.81 47.4,54.64 47.4,48.41 47.09,48.11 | v52.17,62.92 51.22,62.92 | IC3.5 C59.2 | C59.2 84.96,16.62 83.26,16.62 82.45,17.43 82.45,28.14 SV4.1 SV4.2 71.68,31.67 70.87,32.49 C38.2 C23.2 62.87,33.36 62.7,33.2 C42.1 C43.1 C44.1 61.92,28.12 v61.92,16.24 v61.92,16.23 | 32.87,67.23 32.87,69.57 32.48,69.96 32.48,73.69 | 32.48,73.69 C52.1 | 104.44,31.67 103.48,31.67 103.48,30.79 101.17,30.79 101.17,38.98 T5.E 93.34,38.98 93.24,39.08 R55.1 89.85,39.08 87.73,41.2 | 104.44,31.67 105.31,31.67 105.46,31.52 105.46,29.06 105.05,28.65 104.52,28.65 R44.2 R60.1 108.43,27.9 108.57,27.76 v109.65,27.76 | v5.64,9.8 11.89,9.8 | SV5.3 38.35,2.21 38.2,2.06 12.29,2.06 11.89,2.46 11.89,9.8 | v18.82,27.23 19.68,28.09 19.68,35.86 21.29,37.47 25.04,37.47 25.25,37.67 25.25,37.82 25.67,38.24 C29.2 C26.2 29.08,39.24 29.5,39.66 42.19,39.66 43.19,38.66 44.93,38.66 45.23,38.97 | v44.32,30.07 44.32,29.39 43.92,28.98 42.37,28.98 36.02,22.63 36.02,20.7 36.42,20.29 v38.35,20.29 38.94,20.88 C37.2 C28.2 v39.5,23.04 | v23.95,68.78 17.07,68.78 15.47,67.18 C66.2 15.47,64.82 v5.66,64.82 5.66,60.86 4.75,59.95 SV1.1 | 90.3,62.43 100.81,62.43 101.42,63.04 | 108.84,60 106.1,62.74 101.73,62.74 101.42,63.04
  Top 0.152: 32.48,73.69 C55.1 | v61.92,16.23 v53.37,16.23 53.37,14.66 53.15,14.45 Y1.2 51.65,14.45 C12.2 C8.2 | v23.95,68.78 23.95,67.34 24.36,66.93 v29.97,66.93 32.66,66.93 32.87,67.13 32.87,67.23 | v60.15,68.89 61.78,67.25 C32.1 61.88,62.92 C46.1 63.3,60.76 64.89,59.17 U$8.4 64.89,53.82 65.3,53.4 C18.2 C30.2 | v83.44,44.2 86.47,44.2 86.88,43.79 86.88,41.62 87.3,41.2 87.73,41.2 | 38.08,66.93 40.7,64.3 C35.1 40.8,62.92 C49.1 | v23.95,68.78 23.52,69.22 23.36,69.22 22.95,69.62 C48.1 | 101.42,63.04 SV7.2 | 38.08,66.93 33.17,66.93 32.87,67.23 | T2.E 13.42,29.49 13.62,29.29 17.83,29.29 18.03,29.49 R46.2 v18.03,31.47 | v60.15,68.89 v60.15,71.96 61.8,71.96 62.6,72.76 C62.1 68.28,73.71 69.88,72.11 69.88,67.82 70.29,67.4 C45.1 74.4,67.4 74.8,67.81 R42.1 75.59,68.8 75.69,68.7 T1.E | v30.86,60.76 C51.1 29.5,62.88 29.54,62.92 C36.1 | R62.1 R63.1 113.91,13.3 114.71,14.1 C70.2 115.7,20.74 115.77,20.82 C69.2 117.04,20.82 117.04,19.38 | C21.1 C41.1 34.2,55.92 v34.21,55.93 | T3.E 63.93,15.12 63.78,15.27 63.78,15.71 R30.1 62.99,16.23 v61.92,16.23 | 51.22,62.92 C33.1 | C24.2 C25.2 83.52,45.21 83.52,44.27 v83.44,44.2 | C27.1 C34.1 v31.75,27.23 | C63.1 53.67,73.71 53.64,73.69 C60.1 52.84,72.68 v52.83,72.67 | 38.08,66.93 38.38,67.23 v38.38,68.89 U$4.1 | T4.E 96.44,9.04 94.8,9.04 R53.1 94.8,7.38 94.59,7.16 91.61,7.16 88.43,10.34 88.43,15.59 88.01,16.01 C39.2 86.05,16.01 85.95,16.11 C59.2 | C59.2 | IC3.5 | X5.5 11.68,18.26 12.5,17.45 12.5,10.74 11.89,10.13 11.89,9.8 | v109.65,27.76 108.79,26.9 U$7.5 | IC3.5 81.71,16.11 81.55,15.95 81.55,15.58 81.13,15.16 IC3.2 | v60.15,68.89 U$6.1 | v109.65,27.76 110.64,27.76 110.87,27.99 IC1.7 110.87,29.59 111.08,29.81 C68.2 114.3,29.81 114.35,29.86 C67.2 115.52,29.87 116.69,29.87 116.69,27.74 R19.2
  Top 0.152: 90.3,62.43 90.28,62.45 IC2.8 | 87.99,59.85 IC2.4 | 45.23,38.97 45.54,38.66 U4.40 | 45.23,38.97 U4.59 45.23,45.49 45.06,45.66 45.06,47.3 45.87,48.11 47.09,48.11 | v44.32,30.07 45.14,30.07 46.73,31.67 46.73,34.56 48.34,36.16 U4.35 | v44.32,30.07 44.32,30.66 44.23,30.75 U4.20 | 47.09,48.11 47.4,47.8 47.4,45.66 47.23,45.49 U4.55 | C56.1 40.47,74.19 v41.53,74.19 43.64,74.19 44.14,73.69 C58.1 45,69.56 v45.67,68.89 U$5.1 | v83.44,44.2 83.41,44.17 Y2.2 | v109.65,27.76 109.65,28.49 109.57,28.57 IC1.5 | v23.95,68.78 24.79,68.78 24.89,68.89 U$2.1 | T7.E 104.44,32.83 104.44,31.67 | 117.04,19.38 C10.1 119.66,19.38 | T6.E 117.04,17.18 117.04,19.38
  Top 0.457: v96.42,6.25 96.44,6.25 T4.E
  Top 0.61: R39.2 C11.- 119.38,58.6 118.96,58.18 C17.2 | 122.94,77.27 C3.- 119,77.27 118.58,76.85 C16.2 | 123.06,77.39 R6.2 126.69,79.15 v126.69,79.15 | 121.67,65 125.07,65 | v120.37,9.83 125.15,9.83
  Bottom 0.152: 38.66,10.08 45.24,10.08 46.84,11.68 46.84,14.63 48.44,16.23 v53.37,16.23 | v5.66,64.82 1.83,68.66 1.83,82.45 2.23,82.86 SV2.1 | v5.64,9.8 15.24,9.8 18.41,6.63 ICSP.3 | v18.03,31.47 18.03,27.43 18.24,27.23 v18.82,27.23 v20.04,27.23 v31.75,27.23 35.31,27.23 v39.5,23.04 | v60.15,71.96 53.54,71.96 v52.83,72.67 52.83,75.62 48.84,75.62 45.67,72.44 v45.67,68.89 | v41.53,74.19 41.53,70.48 39.93,68.89 v38.38,68.89 38.38,63.73 39.19,62.92 v52.17,62.92 | SV5.3 38.35,9.78 38.66,10.08 | v29.97,66.93 30.86,66.04 v30.86,60.76 v30.86,59.31 30.86,57.53 32.46,55.93 v34.21,55.93 | SV4.2 v83.44,44.2 | v38.35,20.29 38.35,10.39 38.66,10.08
  Bottom 0.457: v120.37,9.83 119.76,9.83 119.76,1.73 96.42,1.73 v96.42,6.25
  other vias: 127.84,64.82 127.84,9.83 71.73,75.23 95.28,82.58 39.6,14.05 71.63,7.8 116.92,3.23 92.51,55.68 65.84,62.99 21.77,80.67 46.86,55.63 55.73,61.47 26.92,17.17 18.44,8.86 46.38,4.88 89.89,37.52 118.39,52.83 112.14,38.23 111.18,70.87 118.69,65.43 94.03,59.72 97.18,64.29 18.11,62.66 77.9,65.96 92.08,73.36 53.92,78.69 32.08,77.37 15.65,68.53 40.31,65.05 75.13,61.8 102.01,36.17 37.44,25.7 43.54,25.7 89.81,10.82 106.71,25.37 4.72,29.26 52.07,32.21 113.67,9.83 120.42,31.72 116.18,19.1 115.21,14.1
  pour Top (isolate 0.508): 0,85.9 122.94,85.9 122.94,0.05 0,0.05
  pour Bottom (isolate 0.508): 0,85.9 122.94,85.9 122.94,0.05 0,0.05
MCLR  (via drill 0.33 pad 0.69)  (1 unrouted)
  Top 0.152: 13.33,5.44 13.33,9.96 R15.1 | 13.33,5.44 12.5,5.44 12.5,2.77 12.9,2.36 21.29,2.36 22.1,3.17 22.1,32.72 v22.73,33.35 | 13.33,5.44 ICSP.1 | v34.44,49.38 v41.71,49.38 | v22.73,44.22 19.66,44.22 v13.59,50.29 | v42.11,38.66 U4.9
  Bottom 0.152: v42.11,38.66 42.11,41.81 41.71,42.22 v41.71,49.38 | v13.59,50.29 34.24,50.29 34.44,50.09 v34.44,49.38 | v22.73,33.35 v22.73,44.22
N$1
  Top 0.152: R62.2 110.36,16.89 110.82,17.35 U$7.8
N$2
  Top 0.152: R20.2 C10.2 121.11,19.22
  Top 0.203: 121.26,19.22 121.26,18.44 120.9,18.44 117.99,18.44 T6.B
  Top 0.305: 121.11,19.22 121.26,19.22
N$3
  Top 0.61: J1.1 142.98,39.22 142.98,42.88 F1.2
N$4
  Top 0.152: R2.1 107.7,79.81 | 107.7,79.81 | 107.7,79.81 LED1.C | LED1.C
N$5
  Top 0.152: 144.41,64.05 144.65,63.81 C5.2
  Top 0.305: U$1.C 144.41,64.05 | C5.2 146.81,63.77 U1.8
  Top 0.61: U$1.C 139.7,64.05 138.82,63.17 L5.1
N$6
  Top 0.152: R5.2 107.7,76.76 | 107.7,76.76 | 107.7,76.76 LED5.C | LED5.C
N$7
  Top 0.152: U1.1 145.9,57.53 144.65,58.75 C5.1
N$8
  Top 0.305: U1.3 149.35,56.19 150.06,55.5 151.73,55.5 R8.2
N$9
  Top 0.152: 144.64,80.81 144.65,80.82 C19.2
  Top 0.305: L7.1 138.44,80.19 139.06,80.81 U$3.C 144.64,80.81 | C19.2 146.6,80.78 146.81,80.57 U2.8
N$10
  Top 0.152: U2.1 145.82,74.3 144.65,75.95 C19.1
N$11
  Top 0.305: U2.3 149.35,73.08 149.91,72.47 151.22,72.47 R7.2
N$12
  Top 0.152: R64.2 104.57,22.52 101.4,25.69 101.4,29.6 R44.1 T7.B
N$13
  Top 0.152: R10.2 150.88,77.61 150.62,77.86 U2.5 150.62,81.71 R9.1
N$14
  Top 0.152: 150.62,64.95 R11.1
  Top 0.305: R12.2 150.62,61.1 U1.5 150.62,64.95
N$18  (1 unrouted)
  Top 0.152: U$10.4 137.24,30.18
  Top 0.61: F1.1 115.98,36.65 137.85,36.65 137.85,30.76 137.82,30.76 137.24,30.18 | R40.2 134.9,30.05 134.9,30.23
N$19  (1 unrouted)
  Top 0.152: L9.1 71.7,35.16 71.6,35.06 C38.1 C23.1 68.45,36.56 66.85,38.16 U4.39
N$20
  Top 0.152: L11.2 51.47,56.82 C40.1 C22.1 49.33,52.12 47.73,50.52 U4.54
N$21  (1 unrouted)
  Top 0.152: L8.2 25.25,36.57 25.27,36.54 C29.1 C26.1 30.57,36.54 31.37,37.34 31.37,38.35 32.18,39.16 U4.8
N$22
  Top 0.152: U$7.10 112.85,15.07 112.93,15 R63.2
N$23  (via drill 0.33 pad 0.69)
  Top 0.152: v112.09,21.74 112.09,19.51 111.84,19.25 U$7.9 | v118.57,21.49 R20.1
  Bottom 0.152: v118.57,21.49 117.86,21.74 v112.09,21.74
N$24
  Top 0.152: L10.1 35.9,57.2 C41.2 C21.2 38.35,52.5 39.01,51.84 43.13,51.84 44.73,50.24 U4.60
N$25  (via drill 0.33 pad 0.69)
  Top 0.61: U$11.3 129.9,14.66 U$9.3 128.45,20.55 v128.45,22.86 | v127.53,27.84 129.9,27.84 U$10.3
  Bottom 0.61: v128.45,22.86 127.53,22.86 v127.53,27.84
N$26  (1 unrouted)
  Top 0.152: L12.2 34.51,25.07 C34.2 C27.2 42.92,29.39 43.73,30.2 U4.19
N$27  (1 unrouted)
  Top 0.152: L13.1 42.25,18.72 C37.1 C28.1 44.06,23.04 47.23,26.21 U4.26
N$28
  Top 0.203: U$7.1 120.7,24.82 120.7,30.07 123.03,30.07 R40.1
N$29  (via drill 0.33 pad 0.69)
  Top 0.61: U$11.4 126.9,24.84 126.9,25.02 | 126.9,25.02 126.9,25.07 129.9,25.07 U$9.1 | U$10.1 126.9,32.45 v126.9,32.44 | v125.86,25.02 126.9,25.02
  Bottom 0.61: v126.9,32.44 125.86,32.44 v125.86,25.02
N$30
  Top 0.152: T6.C 117.37,14.66 U$11.2
N$31
  Top 0.152: 27.75,73.69 C52.2 29.3,78.87 29.56,79.13 X1.1 | 27.75,73.69 27.75,68.41 26.95,67.62 U$2.2 | 27.75,73.69 C53.1
N$32  (via drill 0.33 pad 0.69)
  Top 0.152: IC1.8 111.52,27.15 | 111.52,27.15 111.52,26.38 111.84,26.06 U$7.2 v111.84,23.24 | R19.1 112.72,27.74 112.72,27.15 111.52,27.15 | v110.82,20.8 110.82,20.82 R64.1
  Bottom 0.152: v111.84,23.24 111.84,22.63 110.82,22.63 v110.82,20.8
N$33
  Top 0.152: R59.1 R60.2 110.22,29.6 IC1.6
N$34
  Top 0.152: R22.1 12.54,65.67 12.12,66.1 D1.A 11.58,66.75 9.98,68.35 8.58,68.35 7.79,69.15 R1.2 SV2.6
N$35  (via drill 0.33 pad 0.69)
  Top 0.152: U$11.1 119.63,17.2 v119.63,16.16 | v119.63,12.6 R25.1
  Bottom 0.152: v119.63,16.16 v119.63,12.6
N$36
  Top 0.152: R27.2 30.48,71.17 30.07,70.77 30.07,67.82 30.28,67.62 U$2.7
N$37  (via drill 0.33 pad 0.69)
  Top 0.152: C48.2 C53.2 26.05,72.78 25.25,71.98 v24.66,71.98 | v23.95,66.34 U$2.3
  Bottom 0.152: X1.2 24.66,79.02 v24.66,71.98 24.66,67.06 v23.95,66.34
N$42
  Top 0.152: R30.2 64.29,17.41 64.85,16.85 R28.1 66.44,16.85 66.61,16.69 T3.B
N$43
  Top 0.152: R29.2 65.49,12.92 T3.C
N$44
  Top 0.152: R29.1 63.79,12.09 LED2.C
N$45
  Top 0.152: T2.B 14.35,28.44 14.45,28.54 R45.1 R46.1
N$46
  Top 0.152: R32.2 43.76,71.17 44.17,70.77 44.17,67.62 U$4.7
N$47
  Top 0.152: R33.2 54.18,71.3 54.59,70.89 54.59,67.62 U$5.7
N$48
  Top 0.152: R34.2 64.75,71.17 65.56,70.36 65.56,67.82 65.35,67.62 U$6.7
N$50
  Top 0.152: T2.C 8.89,29.39 7.29,30.99 SV1.20
N$51
  Top 0.152: R49.1 13.77,36.17 15.37,37.77 R48.E
N$52
  Top 0.152: 38.77,74.73 38.77,78.36 38.07,79.06 X2.1 | 38.77,74.73 37.62,74.73 37.4,74.51 C54.1 37.4,71.62 35.23,69.44 35.23,67.82 35.43,67.62 U$4.2 | 38.77,74.73 C56.2
N$53  (via drill 0.33 pad 0.69)
  Top 0.152: C55.2 C54.2 v35.7,74.69 v35.71,74.7 | v35.26,66.34 U$4.3
  Bottom 0.152: X2.2 34.57,75.84 v35.71,74.7 37.57,74.7 40.74,71.53 40.74,70.69 40.34,70.28 38.43,70.28 35.26,67.11 v35.26,66.34
N$54
  Top 0.152: X3.1 51.41,79.03 51.14,78.77 C60.2 50.84,73.69 50.84,74.52 50.64,74.73 49.99,74.73 49.77,74.51 C57.1 49.77,68.41 48.97,67.62 U$5.2
N$55  (via drill 0.33 pad 0.69)
  Top 0.152: X3.2 46.7,79.2 C58.2 v46.7,72.66 v46.71,72.64 47.87,72.64 48.07,72.85 C57.2 | v45.67,66.34 U$5.3
  Bottom 0.152: v46.71,72.64 46.71,67.39 v45.67,66.34
N$56
  Top 0.152: C61.1 59.55,78.55 59.92,78.92 X4.1 58.82,81.51 55.83,81.51 55.02,80.7 55.02,79.98 56.5,78.5 C63.2 56.31,73.71 56.31,67.82 56.52,67.62 U$6.2
N$57
  Top 0.152: 57.85,72.97 60.9,72.97 C62.2 | 57.85,72.97 56.62,71.74 56.62,68.38 56.82,68.17 59,68.17 59.41,67.77 59.41,66.55 59.21,66.34 U$6.3 | X4.2 57.85,78.98 C61.2 57.85,72.97
N$58
  Top 0.152: 72.52,70.5 R42.2 75.59,70.5 75.69,70.6 T1.B | 72.52,70.5 C45.2 | 72.52,70.5 R43.1
N$60
  Top 0.152: T1.C 79.2,75.63 SG1.-
N$61  (via drill 0.33 pad 0.69)
  Top 0.152: R49.2 R50.1 11.48,33.53 12.27,33.53 v12.27,39.83
  Bottom 0.152: v12.27,39.83 11.99,39.55 6.55,39.55 5.74,40.36 5.74,52.5 SV1.3
N$62  (via drill 0.33 pad 0.69)
  Top 0.152: v8.2,54.48 13.07,54.48 13.47,54.89 R51.2
  Bottom 0.152: v8.2,54.48 4.27,54.48 3.45,53.67 3.45,37.01 SV1.17
N$63
  Top 0.152: R50.2 8.34,34.66 SV1.18
N$64
  Top 0.152: T4.B 93.47,10.14 R52.2 93.47,8.25 R53.2
N$65
  Top 0.152: T4.C 100.86,9.2 100.99,9.32 JP1.1
N$66
  Top 0.152: 94.49,40.88 92.46,40.88 R55.2 | 94.49,40.88 R54.2 | 94.49,40.88 T5.B
N$67
  Top 0.152: JP2.1 102.34,40.31 101.96,39.93 T5.C
  Bottom 0.152: JP2.1 106.05,40.31 106.45,40.72 106.45,56.62 106.25,56.82 SV3.2
N$68
  Top 0.152: R56.2 106.43,59.11 105.66,58.34 104.39,58.34 SV3.1
N$69
  Top 0.152: R57.2 SV3.3
N$74
  Top 0.152: SV3.4 106.88,51.74 108.48,50.14 108.48,39.61 104.84,35.97 R58.1 102.33,34.67 T7.C
N$75
  Bottom 0.61: J1.2 153.26,41.05 153.26,35.61 J3.2
N$76
  Top 0.61: J3.1 142.09,28.17 142.09,22.84 U$9.4 131.6,22.84
N$77
  Top 0.152: R61.2 107.73,44.5 106.08,42.85 JP2.2
PGEC1  (1 unrouted)
  Top 0.152: U4.15 41.83,35.66 41.83,34.42 41.02,33.6 24.31,33.6 23.5,32.79 ICSP.5
PGED1  (1 unrouted)
  Top 0.152: U4.16 22.55,35.16 20.95,33.56 ICSP.4
RB2  (via drill 0.33 pad 0.69)  (1 unrouted)
  Top 0.152: v32.79,37.24 33.27,36.75 36.7,36.75 37.29,36.16 U4.14 | v29.67,41.15 27.18,43.64 17.14,43.64 SV1.4
  Bottom 0.152: v29.67,41.15 32.79,38.02 v32.79,37.24
RB3  (via drill 0.33 pad 0.69)
  Top 0.152: v42.11,37.8 42.11,36.87 41.91,36.66 U4.13 | v2.56,47.45 2.23,47.78 2.23,50.14 3.05,50.95 SV1.5
  Bottom 0.152: v2.56,47.45 1.98,48.03 1.98,58.02 3.58,59.62 11.18,59.62 15.06,63.5 15.85,63.5 16.05,63.3 16.05,61.01 22.4,54.66 41.94,54.66 43.54,53.06 43.54,39.22 v42.11,37.8
RB4  (via drill 0.33 pad 0.69)
  Top 0.152: v35.28,37.34 35.46,37.16 U4.12
  Bottom 0.152: v35.28,37.34 35.28,50.14 34.47,50.95 SV1.6
RB5  (via drill 0.33 pad 0.69)
  Top 0.152: v2.87,48.41 SV1.7 | v35.87,37.95 36.4,37.95 36.4,37.66 U4.11
  Bottom 0.152: v35.87,37.95 35.87,51.82 34.27,53.42 15.06,53.42 11.15,57.33 3.68,57.33 2.87,56.52 v2.87,48.41
RB6  (via drill 0.33 pad 0.69)  (1 unrouted)
  Top 0.152: v42.65,32.05 42.73,32.14 U4.17
  Bottom 0.152: v42.65,32.05 32.61,32.05 26.26,38.41 26.26,45.24 23.09,48.41 SV1.8
RB7  (via drill 0.33 pad 0.69)  (1 unrouted)
  Top 0.152: v32.89,30.71 42.42,30.71 43.23,31.52 U4.18
  Bottom 0.152: v32.89,30.71 24.48,30.71 21.31,33.88 21.31,37.65 19.71,39.24 4.57,39.24 3.76,40.06 3.76,44.88 SV1.9
RB8  (via drill 0.33 pad 0.69)
  Top 0.152: v43.28,34.54 44.53,34.54 44.73,34.34 U4.21
  Bottom 0.152: v43.28,34.54 43.28,31.85 42.88,31.44 31.52,31.44 25.17,37.8 25.17,42.67 21.97,45.87 SV1.10
RB9  (via drill 0.33 pad 0.69)
  Top 0.152: v44.37,35.71 45.23,34.85 U4.22 | v3.45,55.07 1.93,53.54 1.93,46.15 SV1.11
  Bottom 0.152: v3.45,55.07 3.45,56.21 4.27,57.02 7.98,57.02 8.79,56.21 8.79,53.54 7.19,51.94 6.86,51.94 6.04,51.13 6.04,50.52 6.86,49.71 27.43,49.71 33.78,43.36 33.78,37.31 35.38,35.71 v44.37,35.71
RB10  (via drill 0.33 pad 0.69)  (1 unrouted)
  Top 0.152: v19.1,43.05 v19.1,28.65 | v45.64,31.75 45.73,31.84 U4.23
  Bottom 0.152: v45.64,31.75 45.64,30.25 44.04,28.65 v19.1,28.65 | v19.1,43.05 9.04,43.05 8.76,43.33 SV1.12
RB11  (via drill 0.33 pad 0.69)  (1 unrouted)
  Top 0.152: v45.14,36.96 46.23,35.86 U4.24 | v37.29,38.53 33.03,38.53 32.22,37.72 32.22,36.28 31.42,35.48 22.25,35.48 20.65,33.88 20.65,25.68 17.47,22.5 8,22.5 6.5,21.01 3.25,21.01 1.65,22.61 1.65,37.69 SV1.13
  Bottom 0.152: v37.29,38.53 38.86,36.96 v45.14,36.96
RB12  (via drill 0.33 pad 0.69)
  Top 0.152: v47.83,30.61 47.55,30.89 47.55,31.93 47.73,32.11 U4.27
  Bottom 0.152: v47.83,30.61 47.83,29.92 49.1,29.92 49.3,30.12 49.3,32.54 48.89,32.94 45.7,32.94 43.51,35.13 33.53,35.13 27.18,41.48 27.18,46.23 24,49.4 6.86,49.4 6.04,48.59 6.04,42.04 SV1.14
RB13  (via drill 0.33 pad 0.69)
  Top 0.152: v48.13,31.44 48.23,31.54 U4.28
  Bottom 0.152: v48.13,31.44 47.4,31.44 45.95,30 45.95,29.41 44.35,27.81 18.75,27.81 18.34,28.22 18.34,30.07 19.02,30.76 19.02,35.66 18.62,36.07 10.54,36.07 9.91,36.7 6.3,36.7 SV1.15
RB14  (via drill 0.33 pad 0.69)
  Top 0.152: v48.72,30.51 48.73,30.52 U4.29
  Bottom 0.152: v48.72,30.51 48.72,31.93 48.31,32.33 44.7,32.33 42.49,30.12 23.81,30.12 20.63,33.3 20.63,35.63 19.84,36.42 14.66,36.42 12.83,38.25 SV1.16
RB15  (via drill 0.33 pad 0.69)  (1 unrouted)
  Top 0.152: v49.3,18.97 49.3,31.47 49.23,31.54 U4.30 | v17.86,26.24 13.87,26.24 12.27,27.84 12.27,30.89 12.47,31.09 15.88,31.09 R45.2
  Bottom 0.152: v17.86,26.24 21.72,22.38 47.7,22.38 49.3,20.78 v49.3,18.97
RC13  (via drill 0.33 pad 0.69)  (1 unrouted)
  Top 0.152: v81.38,34.54 73.76,42.16 U4.47 | v81.38,26.8 v81.38,30.99
  Bottom 0.152: v81.38,30.99 v81.38,34.54 | v81.38,26.8 83.64,26.8 SV4.3
RC14  (1 unrouted)
  Top 0.152: U4.48 78.21,42.66 79.01,41.86 R13.1
RC15  (via drill 0.33 pad 0.69)  (1 unrouted)
  Top 0.152: v54.03,30.02 51.83,30.02 50.23,31.62 U4.32
  Bottom 0.152: v54.03,30.02 54.03,16.06 53.62,15.66 49.06,15.66 47.45,14.05 47.45,12.85 48.26,12.04 85.34,12.04 88.52,15.21 SV4.5
RD0  (via drill 0.33 pad 0.69)  (1 unrouted)
  Top 0.152: v83.52,27.69 83.52,22.71 v93.47,12.75 R52.1 | v79.88,43.26 51.23,43.26 50.83,42.85 50.83,41.87 51.03,41.66 U4.46
  Bottom 0.152: v79.88,43.26 79.88,34.9 76.71,31.72 62,31.72 60.4,30.12 60.4,28.65 60.81,28.25 76.5,28.25 77.06,27.69 v83.52,27.69
RD1  (via drill 0.33 pad 0.69)
  Top 0.152: U4.49 50.23,45.53 50.34,45.64 v73.79,45.64 | v92.73,44.07 94.48,44.07 R54.1
  Bottom 0.152: v73.79,45.64 91.16,45.64 v92.73,44.07
RD2  (via drill 0.33 pad 0.69)
  Top 0.152: U4.50 49.73,46.33 v80.72,46.33 | IC1.2 arc90 IC1.2 v110.87,33.86 | v101.93,46.33 v90.12,46.33
  Bottom 0.152: v110.87,33.86 110.87,31.29 110.64,31.06 109.19,31.06 101.93,38.33 v101.93,46.33 | v90.12,46.33 v80.72,46.33
RD3  (via drill 0.33 pad 0.69)  (1 unrouted)
  Top 0.152: v48.36,41.83 49.23,42.7 U4.51 | v70.61,68.23 70.61,71.46 71.42,72.28 R43.2 | v66.09,56.29 72.67,62.87 v72.67,64.44
  Bottom 0.152: v48.36,41.83 48.54,42.01 48.54,46.28 48.36,46.46 48.36,47.93 48.56,48.13 49.53,48.13 57.68,56.29 v66.09,56.29 | v72.67,64.44 72.67,66.17 v70.61,68.23
RD4  (via drill 0.33 pad 0.69)
  Top 0.152: v48.95,47.55 48.95,46.79 48.7,46.55 48.7,44.53 U4.52 | v65.66,19.56 R28.2
  Bottom 0.152: v65.66,19.56 61.87,19.56 58.7,22.73 58.7,32.39 57.1,33.98 52.3,33.98 49.12,37.16 v49.12,45.8 48.95,45.8 v48.95,47.55
RD5  (via drill 0.33 pad 0.69)
  Top 0.152: v50.67,47.8 50.1,48.38 48.65,48.38 48.23,47.95 U4.53
  Bottom 0.152: v50.67,47.8 58.57,55.7 88.57,55.7 94.92,49.35 94.92,28.65 94.11,27.84 92.35,27.84 SV4.7
RD9  (via drill 0.33 pad 0.69)
  Top 0.152: v54.33,40.26 54.23,40.16 U4.43
  Bottom 0.152: v54.33,40.26 59.23,35.36 69.58,35.36 79,44.78 86.26,44.78 92.61,38.43 92.61,30.12 SV4.9
RD10  (via drill 0.33 pad 0.69)
  Top 0.152: v50.85,40.61 51.54,40.61 51.59,40.66 U4.44
  Bottom 0.152: v50.85,40.61 50.85,41.38 52.45,42.98 53.16,42.98 56.82,39.32 70.86,39.32 76.63,45.08 87.25,45.08 93.6,38.73 SV4.10
RD11
  Top 0.152: R31.1 61.13,40.94 60.91,41.16 U4.45
RE0  (via drill 0.33 pad 0.69)  (1 unrouted)
  Top 0.152: v45.64,46.61 45.73,46.52 U4.58 | SV2.2 R47.2
  Bottom 0.152: SV2.2 16.71,80.31 23.06,73.97 23.06,61.32 29.41,54.97 44.04,54.97 45.64,53.37 v45.64,46.61
RE1  (via drill 0.33 pad 0.69)
  Top 0.152: v32.61,51.54 42.63,51.54 44.23,49.94 U4.61 | v10.46,56.74 9.88,57.33 6.55,57.33 5.74,56.52 5.74,42.75 5.33,42.34 3.23,42.34 1.63,43.94 1.63,77.37 2.03,77.78 SV2.3 R23.2
  Bottom 0.152: v10.46,56.74 15.67,51.54 v32.61,51.54
RE2  (via drill 0.33 pad 0.69)  (1 unrouted)
  Top 0.152: v32.61,48.79 42.92,48.79 43.73,47.98 U4.62 | v9.68,52.22 26.54,52.22 v29.97,48.79 | v9.5,62.94 12.57,59.87 12.57,55.27 12.37,55.07 v9.68,55.07 | SV2.4 R21.2
  Bottom 0.152: v29.97,48.79 v32.61,48.79 | v9.68,55.07 v9.68,52.22 | SV2.4 4.06,74.24 2.95,74.24 2.13,73.43 2.13,71.96 2.95,71.15 6.32,71.15 9.5,67.97 v9.5,62.94
RE3  (via drill 0.33 pad 0.69)  (1 unrouted)
  Top 0.152: v33.2,47.35 42.42,47.35 43.23,46.53 U4.63 | v21.01,58.29 29.26,58.29 30.86,56.69 v30.86,47.35 | SV2.5 v6.78,72.7 R4.2
  Bottom 0.152: v30.86,47.35 v33.2,47.35 | SV2.5 4.06,71.65 4.27,71.45 14.66,71.45 21.01,65.1 v21.01,58.29
RE4  (via drill 0.33 pad 0.69)  (1 unrouted)
  Top 0.152: D1.C 12.12,63.6 12.49,63.97 R22.2 13.33,63.12 13.54,62.92 v15.47,62.92 C66.1 | v42.65,45.77 42.73,45.69 U4.64
  Bottom 0.152: v15.47,62.92 15.47,60.69 21.82,54.34 41.06,54.34 42.65,52.76 v42.65,45.77
RE5  (via drill 0.33 pad 0.69)  (1 unrouted)
  Top 0.152: v87.5,57.76 87.64,57.9 IC2.1 | v40.21,53.77 40.89,53.77 44.07,56.95 v44.07,57.76 | v40.21,45.03 40.21,42.81 39.93,42.81 39.93,42.66 U4.1
  Bottom 0.152: v44.07,57.76 v87.5,57.76 | v40.21,45.03 v40.21,53.77
RE6  (via drill 0.33 pad 0.69)  (1 unrouted)
  Top 0.152: v46.56,52.43 v39.62,52.43 | U4.2 39.78,42.16 39.62,42.32 v39.62,43.38 | v89.71,58.55 IC2.2
  Bottom 0.152: v39.62,43.38 v39.62,52.43 | v89.71,58.55 88.04,56.87 51,56.87 v46.56,52.43
RE7  (via drill 0.33 pad 0.69)  (1 unrouted)
  Top 0.152: v87.27,59.11 87.37,59.2 IC2.3 | v38.2,53.77 38.2,55.5 v41.83,59.13 | v39.04,45.62 41.02,45.62 41.83,44.81 41.83,41.66 U4.3
  Bottom 0.152: v41.83,59.13 87.25,59.13 v87.27,59.11 | v39.04,45.62 38.2,46.46 v38.2,53.77
RF0  (via drill 0.33 pad 0.69)  (1 unrouted)
  Top 0.152: SV5.1 33.27,7.24 33.25,7.26 R18.2 | v47.95,42.98 47.14,42.98 46.73,43.38 U4.56 | v51.33,2.06 55.8,6.53 v55.8,14.86
  Bottom 0.152: v55.8,14.86 55.8,31.95 54.2,33.55 50.85,33.55 47.68,36.73 47.68,42.7 v47.95,42.98 | SV5.1 34.27,3.99 34.27,2.87 35.08,2.06 v51.33,2.06
RF1  (via drill 0.33 pad 0.69)  (1 unrouted)
  Top 0.152: SV5.2 R24.2 | v36.8,20.88 36.8,22.33 43.16,28.68 v46.66,28.68 | v46.33,47.22 46.23,47.12 U4.57
  Bottom 0.152: v46.33,47.22 46.33,36.42 49.51,33.25 49.61,33.25 49.61,29.49 48.79,28.68 v46.66,28.68 | SV5.2 36.8,3.99 v36.8,20.88
RG6
  Top 0.152: R37.1 34.47,46.28 37.64,43.1 37.64,42.77 39.25,41.16 U4.4
RG7
  Top 0.152: U4.5 37.31,40.66 33.86,44.12 R36.1
RG8
  Top 0.152: U4.6 33.78,40.16 32.98,40.96 R35.1
RG9  (via drill 0.33 pad 0.69)  (1 unrouted)
  Top 0.152: v87.91,69.22 87.91,61.15 IC2.6 | v40.82,53.09 41.48,53.09 44.65,56.26 v44.65,63.5 | v39.62,38.25 39.71,38.16 U4.10
  Bottom 0.152: v44.65,63.5 39.5,63.5 38.68,64.31 38.68,65.43 42.98,69.72 42.98,72.75 46.15,75.92 60.22,75.92 66.93,69.22 v87.91,69.22 | v39.62,38.25 40.82,39.45 v40.82,53.09
SCK  (via drill 0.33 pad 0.69)
  Top 0.152: R37.2 31.55,46.28 31.55,61.92 v31.62,62 30.38,63.25 30.38,65.08 U$2.5 | U$6.5 v62.46,65.08 62.46,66.5 62.87,66.9 65.48,66.9 v69.29,70.71 | U$4.5 v42.93,64.24 v42.93,57.66 | v110.03,33.86 110.22,33.67 IC1.3 | v54.86,65.08 U$5.5
  Bottom 0.152: v62.46,65.08 v54.86,65.08 43.76,65.08 v42.93,64.24 | v69.29,70.71 98.68,70.71 98.88,70.51 SV7.3 110.03,57.51 v110.03,33.86 | v31.62,62 35.97,57.66 v42.93,57.66
SCL  (via drill 0.33 pad 0.69)  (1 unrouted)
  Top 0.152: v66.85,27.3 R16.1 | v76,34.16 76,35.69 72.82,38.86 58.75,38.86 57.95,39.66 U4.42
  Bottom 0.152: v76,34.16 60.91,34.16 60.1,33.35 60.1,27.74 60.5,27.33 66.83,27.33 v66.85,27.3
SDA  (via drill 0.33 pad 0.69)  (1 unrouted)
  Top 0.152: v81.99,35.15 81.99,33.98 81.58,33.58 75.51,33.58 75.11,33.98 75.11,35.31 71.93,38.48 55.24,38.48 54.56,39.16 U4.41 | v80.19,31.01 77.44,31.01 74.27,27.84 74.27,25.07 R17.1
  Bottom 0.152: v80.19,31.01 80.19,34.34 81,35.15 v81.99,35.15
SDI  (via drill 0.33 pad 0.69)
  Top 0.152: v32.21,62.84 32.21,55.35 32.03,55.17 32.03,44.12 R36.2 | v52.32,70.18 52.32,71.3 R33.1 51.58,68.52 49.99,66.93 41.57,66.93 41.16,67.34 R32.1 v40.16,71.17 | v61.24,70.18 62.04,70.18 62.24,70.38 R34.1 | v34.21,71.17 R27.1
  Bottom 0.152: SV7.4 96.34,66.9 96.14,66.7 82.53,66.7 80.42,68.81 62.61,68.81 v61.24,70.18 v52.32,70.18 | v32.21,62.84 32.21,69.16 v34.21,71.17 v40.16,71.17
SDO  (via drill 0.33 pad 0.69)
  Top 0.152: v27.63,57.71 30.56,54.79 30.56,48.08 30.28,47.8 30.28,42.16 30.48,41.96 R35.2 | v108.84,32.84 108.86,32.86 IC1.4
  Bottom 0.152: v27.63,57.71 27.63,75.46 33.98,81.81 61.97,81.81 68.32,75.46 68.32,70.59 69.11,69.8 89.51,69.8 90.65,68.66 92.51,68.66 | 92.51,68.66 92.51,70.21 92.71,70.41 96.93,70.41 97.33,70 97.33,67.23 98.93,65.63 100.71,65.63 108.84,57.51 v108.84,32.84 | 92.51,68.66 SV7.5
UART_VCC
  Top 0.152: SV5.4 40.89,7.44 37.71,10.63 R24.1 R18.1 33.25,11.38 33.17,11.46 JP3.2
USBID  (via drill 0.33 pad 0.69)
  Top 0.152: v33.5,18.92 33.5,25.91 33.35,26.06 31.67,26.06 30.86,26.87 30.86,31.04 32.46,32.64 41.33,32.64 42.14,33.45 42.14,34.54 42.7,35.1 42.7,36.06 44.3,37.66 U4.38 | v16.99,11.58 16.99,15.89 13.82,19.06 X5.4
  Bottom 0.152: v16.99,11.58 31.34,11.58 32.16,12.39 32.16,17.58 v33.5,18.92

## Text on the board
tPlace: + | - | + | - | + | - | + | - | OPEN | *1 | POWER LEDS | 0.1uF | 100R | 3V3 PWR | 1.1uH | 3V3 | 4.7k | 0R | 0.1uF | 0R | 4.7k | 5V | 47uF | B330B Schottky | ADP2302 / -3.3V | OVEN TC#1 | OVEN TC#2 | PCB TC#1 | PCB TC#2 | 240R | 4.7k | BUZZER | 390R | 40L | KEYBOARD | 4.7k | .01uF | .01uF | .01uF | .01uF | .01uF | .01uF | .01uF | .01uF | .01uF | .01uF | .01uF | .01uF | 47uF | 10k | 20R | 20R | 20R | 20R | 10uF | 10K | 4.7k | * | * | * | * | 47uF | NPN | 100k | 3.3uF | MAX31855 | MAX31855 | ??uF | SDO | SDI | SCK | GND | 3V3 | OPEN | MAX31855 | MAX31855 | 0.1uF | 1N914 | 0.1uF | 0.1uF | 0.1uF | 0.1uF | 1.1uH | LEDS | 5V0 PWR | 10uF | 10uF | 10uF | 10uF | THERMOCOUPLES | *1 | 0R | 0R | 74HC138 | 0.1uF | B330B Schottky | ADP2302 / -5.0V | 47uF | 10k | * | 330R | 10uH | 10uH | COLD JUNC TEMP | .1uF | 40L | 47uF | .01uF | .01uF | 4.7k | 10uF | 10K | DS18B20 | 330R | 47uF | .1uF | .1uF | .01uF | 0.1uF | RTC CLOCK | SCK | 0.1uF | HEATER | 50R | 1k | 100R | SDI | .01uF | 50R | * | PIN 1 | *1 | LCD INTERFACE | SDO | 50R | DISPLAY | 32.768Khz | 20R | 50R | 10k | PIC32MZEF | NPN | 1.5A - 5x20mm | .1uF | .01uF | 10uH | 120VAC IN | 4.7k | 4.7k | 10uH | .01uF | .1uF | SPARE I/O PINS | 10k | N-FET | GND | 5V | 3.3V | RD10 | 1k | 10uF | NPN | * | 0.1uF | .1uF | 1M ** 200V ** | LCD CONTRAST | 4901 | .01uF | NPN | .1uF | 20R | 2k | 10k | .1uF | 10k | USB INTERFACE | .01uF | GND | RC13 | RC15 | RD5 | RD9 | 10k | 2.2k | 20R | 10uH | 10uF | COOL FAN | 1k | * | 0.1uF | .1uF | 1k | 470uF | 24MHZ CLOCK | 5V | FL5160 | .01uF | POWER LED | 24Cxx EEPROM | N-FET | RS232-VOLTAGE | 10uH | 50R | 10k | 2k | CS7 | CS6 | CS5 | CS4 | 22nF | EEPROM | 10uF | 0.1uF | NPN | SCL | VOM1271 | 5V | 3.3V | 4.7k | 470uF | 470uF | NPN | SDA | 1k | 4.7k | CPU FAN | 1k | 240R | 1k | 100R | 0.01uF | .01uF | NPN | 0.01uF | 1k | 10k | 4.7k | 4.7k | 0.1uF | *1 | 10k | T962A CONTROLLER | MCLR | 3V3 | GND | PGED1 | PGEC1 | TX | RX | GND | 5V | 9VAC IN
